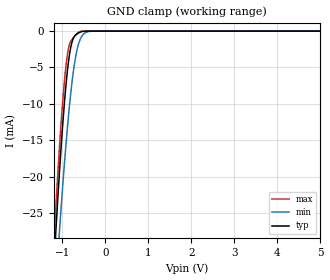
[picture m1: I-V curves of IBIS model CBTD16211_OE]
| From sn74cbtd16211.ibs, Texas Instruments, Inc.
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| Model CBTD16211_OE
| Model CBTD16211_IO
| Model CBTD16211_IO_S
[Model]   CBTD16211_OE
Model_type  Input
Vinl = 0.8
Vinh = 2.0
| variable   typ   min   max
C_comp   1.31pF   1.01pF   1.51pF
[Temperature Range]   40   100   -40
| Ambient temperature   25   85   -40
[Voltage range]   5   4.5   5.5
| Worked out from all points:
|   GND clamp passes 1 mA (typ) near -0.75 V on its own axis
[GND Clamp]
| CBTD16211_OE_50
|   Voltage   I(typ)   I(min)   I(max)
-5V       -499.3mA   -428.8mA   -513.4mA
-1.185V   -30.81mA   -37.7mA    -27.5mA
-1.155V   -27.73mA   -35mA      -24.37mA
-1.06V    -18.58mA   -26.73mA   -15.19mA
-975mV    -11.45mA   -19.87mA   -8.323mA
-900mV    -6.36mA    -14.39mA   -3.919mA
-845mV    -3.6mA     -10.81mA   -2.035mA
-780mV    -1.566mA   -7.177mA   -1.179mA
-695mV    -555uA     -3.606mA   -542.6uA
-605mV    -197.1uA   -1.402mA   -101.7uA
-300mV    -29.19nA   -9.901uA   -1.516nA
5V        5.272nA    13.63nA    5.224nA
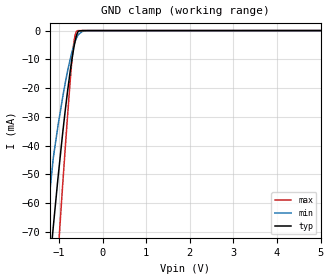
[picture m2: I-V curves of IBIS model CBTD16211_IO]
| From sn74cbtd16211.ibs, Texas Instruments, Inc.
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[Model]   CBTD16211_IO
Model_type  Terminator
| variable   typ   min   max
C_comp   5.18pF   4.50pF   5.90pF
| C_tri-state   5.18pF   4.50pF   5.90pF
[Temperature Range]   40   100   -40
| Ambient temperature   25   85   -40
[Voltage range]   5   4.5   5.5
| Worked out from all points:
|   GND clamp passes 1 mA (typ) near -0.58 V on its own axis
[GND Clamp]
| CBTD16211_IO
|   Voltage   I(typ)   I(min)   I(max)
-5V       -2.642A    -2.758A    -2.291A
-1.295V   -99.46mA   -69.29mA   -145.7mA
-1.13V    -68.07mA   -44.15mA   -103.8mA
-1.02V    -50.78mA   -32.8mA    -77.36mA
-915mV    -35.56mA   -23.09mA   -53.47mA
-805mV    -21.25mA   -14.23mA   -29.98mA
-710mV    -10.66mA   -7.893mA   -11.38mA
-680mV    -7.768mA   -6.2mA     -6.702mA
-630mV    -3.651mA   -3.782mA   -1.554mA
-575mV    -682.7uA   -1.845mA   -37.09uA
-360mV    -273.5nA   -16.17uA   -7.084nA
5V        177.3pA    476.9pA    151.1pA
